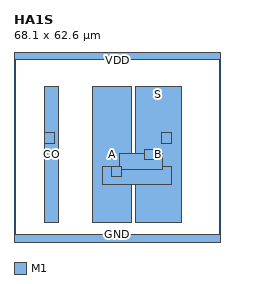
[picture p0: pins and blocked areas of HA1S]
MACRO HA1S
  CLASS CORE ;
  ORIGIN 0 0 ;
  SIZE 68.100 BY 62.600 ;
  SYMMETRY X Y ;
  SITE TR1um_site ;
  PIN CO
    DIRECTION OUTPUT ; USE SIGNAL ;
    PORT
      LAYER M1 ;
        RECT 10.100 6.400 14.700 51.200 ;
      LAYER M1 ;
        RECT 10.100 32.600 13.500 36.000 ;
    END
  END CO
  PIN S
    DIRECTION OUTPUT ; USE SIGNAL ;
    PORT
      LAYER M1 ;
        RECT 40.100 6.400 55.100 51.200 ;
      LAYER M1 ;
        RECT 48.600 32.600 52.000 36.000 ;
    END
  END S
  PIN B
    DIRECTION INPUT ; USE SIGNAL ;
    PORT
      LAYER M1 ;
        RECT 40.100 6.400 55.100 51.200 ;
      LAYER M1 ;
        RECT 34.900 23.800 49.000 29.200 ;
      LAYER M1 ;
        RECT 43.100 27.100 46.500 30.500 ;
    END
  END B
  PIN A
    DIRECTION INPUT ; USE SIGNAL ;
    PORT
      LAYER M1 ;
        RECT 29.300 19.000 51.900 25.000 ;
      LAYER M1 ;
        RECT 26.000 6.400 38.700 51.200 ;
      LAYER M1 ;
        RECT 32.100 21.600 35.500 25.000 ;
    END
  END A
  PIN GND
    DIRECTION INOUT ; USE GROUND ;
    PORT
      LAYER M1 ;
        RECT 0.000 0.000 68.100 2.600 ;
    END
  END GND
  PIN VDD
    DIRECTION INOUT ; USE POWER ;
    PORT
      LAYER M1 ;
        RECT 0.000 60.000 68.100 62.600 ;
    END
  END VDD
END HA1S
